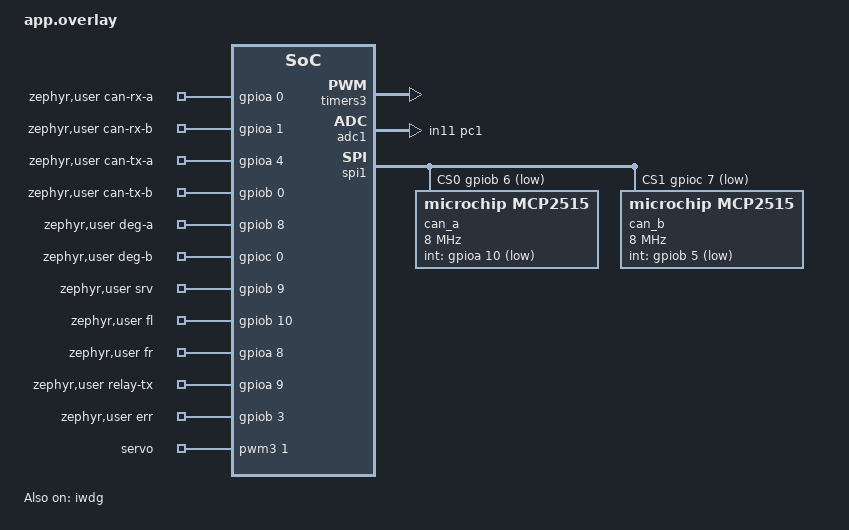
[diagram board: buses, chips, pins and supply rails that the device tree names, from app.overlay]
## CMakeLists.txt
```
cmake_minimum_required(VERSION 3.20.0)

find_package(Zephyr REQUIRED HINTS $ENV{ZEPHYR_BASE})
project(node2_front)

target_include_directories(app PRIVATE ${CMAKE_CURRENT_SOURCE_DIR}/../shared)

target_sources(app PRIVATE
    ${CMAKE_CURRENT_SOURCE_DIR}/../shared/raft_agent.c
    ${CMAKE_CURRENT_SOURCE_DIR}/../shared/raft_transport.c
    # shared with node3_rear (identical files)
    src/main.c
    src/blink.c
    src/button.c
    src/canbus.c
    src/ctrl.c
    src/current_sensor.c
    src/evlog.c
    src/hb.c
    src/relay.c
    src/raft_node.c
    src/report.c
    src/tp.c
    src/wcet.c
    src/jitter.c
    src/watchdog.c
    src/zone.c
    # N2 only: steering zone
    src/servo.c
    src/steer.c
)
```

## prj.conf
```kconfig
CONFIG_GPIO=y
CONFIG_SPI=y
CONFIG_CAN=y
# RX overrun counter in the 1 s summary (ovr=)
CONFIG_STATS=y
CONFIG_CAN_STATS=y
# CONFIG_CAN_MCP2515 is turned on automatically by the mcp2515 nodes in app.overlay
CONFIG_PWM=y
CONFIG_ADC=y
# Independent watchdog (R4.5) and reset-cause readout
CONFIG_WATCHDOG=y
CONFIG_HWINFO=y

CONFIG_CONSOLE=y
CONFIG_UART_CONSOLE=y
CONFIG_PRINTK=y

CONFIG_MAIN_STACK_SIZE=2048

# WCET measurement (src/wcet.c): per-thread CPU time, which stops while a
# thread is preempted or blocked. ANALYSIS adds the driver threads' longest run.
CONFIG_THREAD_RUNTIME_STATS=y
CONFIG_SCHED_THREAD_USAGE=y
CONFIG_SCHED_THREAD_USAGE_ANALYSIS=y
```

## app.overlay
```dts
/*
 * N2 (front, steering): two MCP2515 CAN modules on SPI1, the Lab 2 steering
 * servo and servo current sensor, and the Lab 3 test points.
 * Full pin and breadboard-row map: docs/lab3_pin_map.md
 */
#include <zephyr/dt-bindings/gpio/gpio.h>
#include <zephyr/dt-bindings/pwm/pwm.h>

/ {
	aliases {
		can-a = &can_a;
		can-b = &can_b;
	};

	zephyr,user {
		/* Test points (src/tp.c). Rows 1-2 of the test-point board are GND. */
		can-rx-a-gpios = <&gpioa 0 GPIO_ACTIVE_HIGH>;	/* row 3:  CAN_RX_A, A0 / PA0 */
		can-rx-b-gpios = <&gpioa 1 GPIO_ACTIVE_HIGH>;	/* row 4:  CAN_RX_B, A1 / PA1 */
		can-tx-a-gpios = <&gpioa 4 GPIO_ACTIVE_HIGH>;	/* row 5:  CAN_TX_A, A2 / PA4 */
		can-tx-b-gpios = <&gpiob 0 GPIO_ACTIVE_HIGH>;	/* row 6:  CAN_TX_B, A3 / PB0 */
		deg-a-gpios    = <&gpiob 8 GPIO_ACTIVE_HIGH>;	/* row 7:  DEG_A,    D15 / PB8, LED */
		deg-b-gpios    = <&gpioc 0 GPIO_ACTIVE_HIGH>;	/* row 8:  DEG_B,    A5 / PC0, LED */
		srv-gpios      = <&gpiob 9 GPIO_ACTIVE_HIGH>;	/* row 9:  SRV,      D14 / PB9: toggles on each servo duty set (servo PWM itself: D5 / PB4) */
		fl-gpios       = <&gpiob 10 GPIO_ACTIVE_HIGH>;	/* row 10: FL,       D6 / PB10, LED */
		fr-gpios       = <&gpioa 8 GPIO_ACTIVE_HIGH>;	/* row 11: FR,       D7 / PA8,  LED */
		relay-tx-gpios = <&gpioa 9 GPIO_ACTIVE_HIGH>;	/* row 12: RELAY_TX, D8 / PA9 */
		err-gpios      = <&gpiob 3 GPIO_ACTIVE_HIGH>;	/* row 13: ERR,      D3 / PB3 */

		/* Steering servo (src/servo.c), 50 Hz, as in Lab 2 */
		pwms = <&pwm3 1 PWM_MSEC(20) PWM_POLARITY_NORMAL>;
		pwm-names = "servo";
	};
};

/* ---- Board defaults that sit on pins this node uses ---- */
/* ---- Independent watchdog (src/watchdog.c); the window watchdog stays off ---- */
&iwdg { status = "okay"; };
&wwdg { status = "disabled"; };

&usart1 { status = "disabled"; };	/* PB6/PB7: PB6 is CAN A chip select */
&i2c1 { status = "disabled"; };		/* PB8/PB9: DEG_A, SRV */
&i2c3 { status = "disabled"; };		/* PA8/PC9: PA8 is FR */
&pwm2 { status = "disabled"; };		/* PWM LED on PA5 = SPI1 SCK */
&timers2 { status = "disabled"; };

/* ---- Servo PWM on D5 / PB4 (TIM3_CH1), 1 MHz timer tick (Lab 2) ---- */
&timers3 {
	status = "okay";
	st,prescaler = <83>;

	pwm3: pwm {
		status = "okay";
		pinctrl-0 = <&tim3_ch1_pb4>;
		pinctrl-names = "default";
	};
};

/* ---- Servo current sensor: PC1 = ADC1_IN11 (Lab 2) ---- */
&adc1 {
	pinctrl-0 = <&adc1_in11_pc1>;
	pinctrl-names = "default";
	status = "okay";
};

/*
 * ---- Two XIAO CAN modules (MCP2515 + SN65HVD230) on SPI1 ----
 *
 *   Module   Function   Nucleo
 *   D8       SCK        D13 / PA5   (shared)
 *   D10      MOSI       D11 / PA7   (shared)
 *   D9       MISO       D12 / PA6   (shared)
 *   D7       CS         CAN A: D10 / PB6    CAN B: D9 / PC7
 *   D6       INT        CAN A: D2  / PA10   CAN B: D4 / PB5
 *
 * osc-freq must match the crystal printed on the module's metal can.
 */
&spi1 {
	status = "okay";
	cs-gpios = <&gpiob 6 GPIO_ACTIVE_LOW>,	/* reg 0: CAN A */
		   <&gpioc 7 GPIO_ACTIVE_LOW>;	/* reg 1: CAN B */

	can_a: can@0 {
		compatible = "microchip,mcp2515";
		reg = <0>;
		/*
		 * Requests 8 MHz; SPI1 runs from the 84 MHz APB2 clock with power-of-two
		 * dividers, so the real clock is 84/16 = 5.25 MHz (4 MHz gave 2.625).
		 * Lab 5: N2 relays ~190 frames/s over this shared bus; at 2.625 MHz its
		 * TX completions fell behind and heartbeats found all 3 TX buffers busy.
		 * History: 1 MHz lost back-to-back frames. MCP2515 max is 10 MHz.
		 */
		spi-max-frequency = <8000000>;
		int-gpios = <&gpioa 10 (GPIO_ACTIVE_LOW | GPIO_PULL_UP)>;
		osc-freq = <16000000>;
		bitrate = <500000>;
		status = "okay";
	};

	can_b: can@1 {
		compatible = "microchip,mcp2515";
		reg = <1>;
		spi-max-frequency = <8000000>;
		int-gpios = <&gpiob 5 (GPIO_ACTIVE_LOW | GPIO_PULL_UP)>;
		osc-freq = <16000000>;
		bitrate = <500000>;
		status = "okay";
	};
};
```

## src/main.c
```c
/*
 * Lab 3 zone controller: shared dual-CAN layer, heartbeats, HB_MON with
 * degraded LEDs and zone failure, the N2 relay, test points, and the Lab 2
 * actuators and sensors for this zone (app.h: steer.c on N2, drive.c on N3).
 *
 * Threads (priority, lower = higher; all values in lab3_config.h):
 *   MCP2515 driver x2 (2)  SPI frame reads, toggles CAN_RX_A/B via canbus rx_cb
 *   relay      (3, N2)     forwards first copies to the other bus, RELAY_TX
 *   dispatch   (4)         dedup by (ID, seq), heartbeat ages, CTRL check,
 *                          HB/FAULT -> zone state, BLINK -> blink
 *   steer      (5, N2)     CTRL -> servo angle
 *   drive      (5, N3)     CTRL -> brake / coast / PID target
 *   blink      (5)         this zone's two blinker lamps
 *   test_btn   (5)         USER button B1 -> local fault / recover
 *   pid        (6, N3)     encoders -> motor duty every 10 ms
 *   hb_tx      (7)         HB every 20 ms on both buses
 *   hb_mon     (8)         every 5 ms: DEG_A/B, zone lost, zone state, ERR, watchdog
 *   force      (9, N2)     FORCE every 50 ms
 *   current    (10)        current sensors every 20 ms
 *   report     (12)        console summary once a second
 *
 * Console: USART2 / ST-LINK virtual COM port, 115200 baud.
 */
#include <zephyr/kernel.h>
#include <zephyr/sys/printk.h>

#include "app.h"
#include "blink.h"
#include "button.h"
#include "canbus.h"
#include "ctrl.h"
#include "hb.h"
#include "lab3_config.h"
#include "node_config.h"
#include "raft_node.h"
#include "raft_config.h"
#include "relay.h"
#include "report.h"
#include "tp.h"
#include "watchdog.h"
#include "wcet.h"
#include "zone.h"

/* Dispatch thread: route the first copy of each frame. */
static void on_frame(const struct can_frame *frame, int bus)
{
	if (catalog_is_raft(frame->id)) {
		raft_node_receive(frame);
		return;
	}
	if (frame->id == ID_CTRL) {
		ctrl_on_frame(frame);
	} else if (frame->id == ID_BLINK) {
		blink_on_frame(frame);
	} else if (catalog_is_hb(frame->id) || (frame->id >= ID_FAULT(0) && frame->id < ID_FAULT(NUM_NODES))) {
		zone_on_frame(frame);
	}
	app_on_frame(frame, bus);
}

int main(void)
{
	printk("Lab 3 zone %s: heartbeat 0x%03x every %d ms, relay %s\n", NODE_NAME,
	       ID_HB(NODE_SELF), HB_PERIOD_MS, RELAY_ENABLED ? "on" : "off");

	tp_init();
	wcet_init();
	if (TP_WALK_MS > 0) {
		tp_selftest(TP_WALK_MS);
	}
	/* Power up in the error state with both buses degraded until heartbeats arrive. */
	tp_set(TP_ERR, 1);
	tp_set(TP_DEG_A, 1);
	tp_set(TP_DEG_B, 1);

	canbus_set_handler(on_frame);
	if (canbus_init() < 0) {
		printk("no CAN controller came up\n");
	}
	raft_node_init();
	relay_init();
	hb_init();
	report_init();

	/* Actuators safe, sensors calibrated (~0.75 s), then the zone's tasks. */
	int ret = app_init();

	if (ret < 0) {
		printk("app_init failed (%d): actuators stay in their safe state\n", ret);
	}
	blink_init();
	if (button_init() < 0) {
		printk("test button init failed\n");
	}
	/* Last, and only if the actuator task is running: it has to check in. */
	if (ret == 0) {
		watchdog_init();
	} else {
		printk("watchdog not started (no actuator task to supervise)\n");
	}
	return 0;
}
```

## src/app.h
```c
/*
 * Node-specific application, implemented by steer.c (N2) or drive.c (N3).
 * main.c and report.c are shared and call these.
 */
#ifndef APP_H
#define APP_H

#include <zephyr/drivers/can.h>

/* Puts actuators in their safe state, calibrates sensors, starts the tasks. */
int app_init(void);

/* Called by the dispatch thread with the first copy of each catalog frame. */
void app_on_frame(const struct can_frame *frame, int bus);

/* One or two lines for the once-a-second console summary. */
void app_report(void);

#endif /* APP_H */
```

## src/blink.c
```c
#include "blink.h"

#include <zephyr/kernel.h>
#include <zephyr/sys/atomic.h>

#include "catalog.h"
#include "evlog.h"
#include "hb.h"
#include "lab3_config.h"
#include "node_config.h"
#include "tp.h"
#include "wcet.h"
#include "zone.h"

#define BLINK_STACK_SIZE 1024

static atomic_t last_bits;      /* byte 1 of the last BLINK */
static atomic_t last_rx_ms;     /* 0 = never */
static atomic_t local_hazard;
static atomic_t lamps;          /* bit 0 left, bit 1 right: what's lit now */

K_SEM_DEFINE(blink_new, 0, 1);
K_THREAD_STACK_DEFINE(blink_stack, BLINK_STACK_SIZE);
static struct k_thread blink_data;

void blink_on_frame(const struct can_frame *frame)
{
	uint32_t now = k_uptime_get_32();

	atomic_set(&last_bits, frame->data[1]);
	atomic_set(&last_rx_ms, now != 0 ? now : 1);
	k_sem_give(&blink_new);
}

static void set_lamps(bool left, bool right)
{
	tp_set(BLINK_LAMP_LEFT, left);
	tp_set(BLINK_LAMP_RIGHT, right);
	atomic_set(&lamps, (left ? 1 : 0) | (right ? 2 : 0));
}

static void blink_thread(void *p1, void *p2, void *p3)
{
	uint32_t next_local_toggle = 0;
	bool local_phase = false;
	uint8_t logged_mode = 0;
	struct wcet_job job = WCET_JOB(WCET_BLINK);

	ARG_UNUSED(p1);
	ARG_UNUSED(p2);
	ARG_UNUSED(p3);

	for (;;) {
		/* A frame wakes us at once; otherwise re-check every 10 ms. */
		wcet_end(&job);
		k_sem_take(&blink_new, K_MSEC(10));
		wcet_begin(&job);

		uint32_t now = k_uptime_get_32();
		uint32_t rx = (uint32_t)atomic_get(&last_rx_ms);
		bool hazard_here = zone_state() == ZONE_ISOLATED || !hb_peer_alive(NODE_N1) ||
				   rx == 0 || now - rx > BLINK_STALE_MS;

		if (hazard_here) {
			if (!atomic_get(&local_hazard)) {
				if (zone_state() == ZONE_ISOLATED) {
					evlog("local hazard ON: zone ISOLATED");
				} else if (!hb_peer_alive(NODE_N1)) {
					evlog("local hazard ON: N1 heartbeat lost");
				} else if (rx == 0) {
					evlog("local hazard ON: no BLINK received yet");
				} else {
					evlog("local hazard ON: no BLINK for %u ms", now - rx);
				}
				atomic_set(&local_hazard, 1);
				local_phase = true;
				next_local_toggle = now + BLINK_HALF_MS;
			} else if ((int32_t)(now - next_local_toggle) >= 0) {
				local_phase = !local_phase;
				next_local_toggle += BLINK_HALF_MS;
			}
			set_lamps(local_phase, local_phase);
			continue;
		}
		if (atomic_get(&local_hazard)) {
			evlog("local hazard off");
		}
		atomic_set(&local_hazard, 0);

		uint8_t bits = (uint8_t)atomic_get(&last_bits);
		uint8_t mode = bits & (BLINK_LEFT | BLINK_RIGHT);

		if (mode != logged_mode) {
			static const char *const names[] = {"off", "LEFT", "RIGHT", "HAZARD"};

			evlog("cockpit BLINK %s -> %s", names[logged_mode], names[mode]);
			logged_mode = mode;
		}
		bool on = bits & BLINK_PHASE;

		set_lamps(on && (bits & BLINK_LEFT), on && (bits & BLINK_RIGHT));
	}
}

const char *blink_describe(void)
{
	static const char *const names[] = {"off", "LEFT", "RIGHT", "HAZARD"};
	static char buf[32];
	uint8_t bits = (uint8_t)atomic_get(&last_bits) & (BLINK_LEFT | BLINK_RIGHT);
	bool local = atomic_get(&local_hazard);
	int l = (int)atomic_get(&lamps);

	snprintk(buf, sizeof(buf), "%s%s, lamps %s", local ? "HAZARD" : names[bits],
		 local ? " (local)" : "", l == 3 ? "both on" : (l == 1 ? "L on" : (l == 2 ? "R on" : "off")));
	return buf;
}

int blink_init(void)
{
	k_thread_create(&blink_data, blink_stack, K_THREAD_STACK_SIZEOF(blink_stack), blink_thread,
			NULL, NULL, NULL, PRIO_BLINK, 0, K_NO_WAIT);
	k_thread_name_set(&blink_data, "blink");
	return 0;
}
```

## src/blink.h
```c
/*
 * BLINK_F (N2) / BLINK_R (N3): this zone's two blinker lamps (BLINK_LAMP_LEFT /
 * BLINK_LAMP_RIGHT in node_config.h).
 *
 * Follows the cockpit's BLINK frames: lamp on = its side's bit set and the
 * phase bit set, updated as soon as a frame arrives (both STM32s act on the
 * same frame, which is the front/rear sync). If N1's heartbeat is lost, the
 * zone is ISOLATED, or no BLINK arrives for BLINK_STALE_MS (2.6 s), the zone
 * flashes its own hazards at 1 Hz. A single lost BLINK only delays one edge.
 */
#ifndef BLINK_H
#define BLINK_H

#include <zephyr/drivers/can.h>

int blink_init(void);

/* Dispatch thread, first copy of each BLINK frame. */
void blink_on_frame(const struct can_frame *frame);

/* For the report: "LEFT on", "HAZARD (local) off", ... */
const char *blink_describe(void);

#endif /* BLINK_H */
```

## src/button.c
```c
/*
 * TEST_BTN: the Nucleo's blue USER button B1 (PC13, the board's sw0). The GPIO
 * interrupt only gives a semaphore; this thread debounces (TEST_BTN_DEBOUNCE_MS
 * lockout after an accepted press, so the first edge acts at once) and hands
 * the press to the zone state machine. Single press = local fail, double
 * press = recover (zone.c).
 */
#include "button.h"

#include <zephyr/drivers/gpio.h>
#include <zephyr/kernel.h>
#include <zephyr/sys/printk.h>

#include "lab3_config.h"
#include "wcet.h"
#include "zone.h"

#define BUTTON_STACK_SIZE 1024

static const struct gpio_dt_spec button = GPIO_DT_SPEC_GET(DT_ALIAS(sw0), gpios);
static struct gpio_callback button_cb;

K_SEM_DEFINE(button_sem, 0, 1);
K_THREAD_STACK_DEFINE(button_stack, BUTTON_STACK_SIZE);
static struct k_thread button_data;

static void button_isr(const struct device *dev, struct gpio_callback *cb, uint32_t pins)
{
	ARG_UNUSED(dev);
	ARG_UNUSED(cb);
	ARG_UNUSED(pins);
	k_sem_give(&button_sem);
}

static void button_thread(void *p1, void *p2, void *p3)
{
	uint32_t last_press = 0;
	bool first = true;
	struct wcet_job job = WCET_JOB(WCET_TEST_BTN);

	ARG_UNUSED(p1);
	ARG_UNUSED(p2);
	ARG_UNUSED(p3);

	for (;;) {
		wcet_end(&job);
		k_sem_take(&button_sem, K_FOREVER);
		wcet_begin(&job);

		uint32_t now = k_uptime_get_32();

		if (!first && now - last_press < TEST_BTN_DEBOUNCE_MS) {
			continue; /* contact bounce */
		}
		first = false;
		last_press = now;
		zone_test_button();
	}
}

int button_init(void)
{
	int ret;

	if (!gpio_is_ready_dt(&button)) {
		return -ENODEV;
	}
	ret = gpio_pin_configure_dt(&button, GPIO_INPUT);
	ret = ret ? ret : gpio_pin_interrupt_configure_dt(&button, GPIO_INT_EDGE_TO_ACTIVE);
	if (ret < 0) {
		return ret;
	}
	gpio_init_callback(&button_cb, button_isr, BIT(button.pin));
	gpio_add_callback(button.port, &button_cb);

	k_thread_create(&button_data, button_stack, K_THREAD_STACK_SIZEOF(button_stack),
			button_thread, NULL, NULL, NULL, PRIO_TEST_BTN, 0, K_NO_WAIT);
	k_thread_name_set(&button_data, "test_btn");
	return 0;
}
```

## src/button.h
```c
/* TEST_BTN on the USER button B1 (PC13). */
#ifndef BUTTON_H
#define BUTTON_H

int button_init(void);

#endif /* BUTTON_H */
```

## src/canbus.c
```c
#include "canbus.h"

#include <string.h>

#include <zephyr/kernel.h>
#include <zephyr/sys/printk.h>

#include "lab3_config.h"
#include "node_config.h"
#include "tp.h"
#include "jitter.h"
#include "wcet.h"

#define DISPATCH_STACK_SIZE 1536
#define RX_QUEUE_DEPTH      32

static const struct device *const can_devs[NUM_BUSES] = {
	DEVICE_DT_GET(DT_ALIAS(can_a)),
	DEVICE_DT_GET(DT_ALIAS(can_b)),
};
static const char bus_name[NUM_BUSES] = {'A', 'B'};
static const enum tp_id tp_rx[NUM_BUSES] = {TP_CAN_RX_A, TP_CAN_RX_B};
static const enum tp_id tp_tx[NUM_BUSES] = {TP_CAN_TX_A, TP_CAN_TX_B};

const uint16_t canbus_slot_id[CANBUS_NUM_SLOTS] = {
	ID_CTRL,
	ID_FAULT(NODE_N1), ID_FAULT(NODE_N2), ID_FAULT(NODE_N3),
	ID_HB(NODE_N1), ID_HB(NODE_N2), ID_HB(NODE_N3),
	ID_BLINK,
	ID_FORCE,
};

/* Hardware filters: masks cover the FAULT and HB ranges in one filter each. */
static const struct can_filter catalog_filters[] = {
	{.id = ID_CTRL, .mask = CAN_STD_ID_MASK},
	{.id = ID_FAULT(0), .mask = 0x7FC}, /* 0x020-0x023 */
	{.id = ID_HB(0), .mask = 0x7FC},    /* 0x100-0x103 */
	/* BLINK 0x200 and FORCE 0x300 differ only in bit 8: one filter keeps us at six. */
	{.id = ID_BLINK, .mask = CAN_STD_ID_MASK & ~(ID_BLINK ^ ID_FORCE)},
	{.id = ID_REF(0), .mask = RAFT_REF_FILTER_MASK},          /* 0x040-0x043 */
	{.id = ID_RAFT_BULK_BASE, .mask = RAFT_BULK_FILTER_MASK}, /* 0x140-0x15F */
};

struct canbus_stats canbus_stats;

static bool bus_running[NUM_BUSES];
static atomic_t bus_degraded[NUM_BUSES];
/*
 * Frames handed to the MCP2515 and not yet completed, per bus. The chip has
 * three TX buffers; bulk Raft fragments may use at most RAFT_TX_MAX_INFLIGHT
 * of them, so a heartbeat, CTRL, or FAULT (sent with K_NO_WAIT) always finds
 * one free. REF is a single periodic frame and is not limited.
 */
static atomic_t tx_inflight[NUM_BUSES];
static atomic_t bus_busoff[NUM_BUSES];

static canbus_handler_t relay_hook;
static uint32_t cur_rx_t; /* dispatch thread: t_rx of the frame being handled */
static canbus_handler_t app_handler;

/* Per-ID send sequence counters. */
static uint8_t tx_seq[CANBUS_NUM_SLOTS];
static struct k_spinlock tx_lock;

/* HB_TX and HB_MON can both flush a bus; one stop/start at a time. */
K_MUTEX_DEFINE(flush_lock);

/* Dispatch thread state (only the dispatch thread writes these). */
struct seen {
	int64_t ms;
	uint8_t seq;
	bool valid;
};
static struct seen seen[CANBUS_NUM_SLOTS];
struct raft_recent {
	uint32_t id;
	int64_t ms;
	uint8_t data[FRAME_DLC];
};
static struct raft_recent raft_recent[32];
static uint8_t raft_recent_next;
/* 32-bit so other threads read it in one access; 0 = never heard. */
static uint32_t last_hb_ms[NUM_BUSES][NUM_NODES];

struct rx_item {
	uint8_t bus;
	uint32_t t_rx; /* k_cycle_get_32() in rx_cb */
	struct can_frame frame;
};
K_MSGQ_DEFINE(rx_q, sizeof(struct rx_item), RX_QUEUE_DEPTH, 4);

K_THREAD_STACK_DEFINE(dispatch_stack, DISPATCH_STACK_SIZE);
static struct k_thread dispatch_thread_data;

static int slot_of(uint32_t id)
{
	for (int i = 0; i < CANBUS_NUM_SLOTS; i++) {
		if (canbus_slot_id[i] == id) {
			return i;
		}
	}
	return -1;
}

static bool raft_duplicate(const struct can_frame *f, int64_t now)
{
	for (size_t i = 0; i < ARRAY_SIZE(raft_recent); i++) {
		if (raft_recent[i].id == f->id && now - raft_recent[i].ms < DUP_WINDOW_MS &&
		    memcmp(raft_recent[i].data, f->data, FRAME_DLC) == 0) {
			return true;
		}
	}
	struct raft_recent *r = &raft_recent[raft_recent_next++ % ARRAY_SIZE(raft_recent)];

	r->id = f->id;
	r->ms = now;
	memcpy(r->data, f->data, FRAME_DLC);
	return false;
}

const struct device *canbus_dev(int bus)
{
	return can_devs[bus];
}

/* MCP2515 driver thread, right after the SPI read: no printing, just queue it. */
static void rx_cb(const struct device *dev, struct can_frame *frame, void *user_data)
{
	struct rx_item item = {.bus = (uint8_t)(uintptr_t)user_data, .frame = *frame};

	ARG_UNUSED(dev);
	item.t_rx = jit_now();
	tp_toggle(tp_rx[item.bus]);
	wcet_driver_seen(item.bus);
	if (k_msgq_put(&rx_q, &item, K_NO_WAIT) != 0) {
		atomic_inc(&canbus_stats.rx_dropped);
	}
}

static void tx_cb(const struct device *dev, int error, void *user_data)
{
	int bus = (int)(uintptr_t)user_data;

	ARG_UNUSED(dev);
	if (atomic_dec(&tx_inflight[bus]) <= 0) {
		atomic_set(&tx_inflight[bus], 0); /* never below zero after a flush */
	}
	atomic_inc(error == 0 ? &canbus_stats.bus[bus].tx_ok : &canbus_stats.bus[bus].tx_err);
}

/* Counts the buffer before can_send() so tx_cb can never run first. */
static int send_counted(int bus, const struct can_frame *frame, k_timeout_t wait)
{
	struct canbus_bus_stats *b = &canbus_stats.bus[bus];
	atomic_val_t now = atomic_inc(&tx_inflight[bus]) + 1;

	if (now > atomic_get(&b->infl_max)) {
		atomic_set(&b->infl_max, now);
	}
	int ret = can_send(can_devs[bus], frame, wait, tx_cb, (void *)(uintptr_t)bus);

	if (ret < 0) {
		atomic_dec(&tx_inflight[bus]);
	} else {
		atomic_inc(&b->tx_queued);
	}
	return ret;
}

static bool is_raft_bulk(uint32_t id)
{
	return catalog_is_raft(id) && (id & ~3u) != ID_REF(0);
}

bool canbus_raft_tx_ready(int bus)
{
	return atomic_get(&tx_inflight[bus]) < RAFT_TX_MAX_INFLIGHT;
}

bool canbus_raft_wait_reserve(int bus)
{
	uint32_t start = k_cycle_get_32();

	while (!canbus_raft_tx_ready(bus)) {
		if (k_cyc_to_us_floor32(k_cycle_get_32() - start) >= RAFT_TX_RESERVE_WAIT_US) {
			return false;
		}
		k_sleep(K_USEC(100));
	}
	return true;
}

long canbus_tx_inflight(int bus)
{
	return (long)atomic_get(&tx_inflight[bus]);
}

static void state_cb(const struct device *dev, enum can_state state, struct can_bus_err_cnt err,
		     void *user_data)
{
	ARG_UNUSED(dev);
	ARG_UNUSED(err);
	if (state == CAN_STATE_BUS_OFF) {
		atomic_set(&bus_busoff[(int)(uintptr_t)user_data], 1);
	}
}

static void dispatch_thread(void *p1, void *p2, void *p3)
{
	struct rx_item item;
	struct wcet_job job = WCET_JOB(WCET_DISPATCH);

	ARG_UNUSED(p1);
	ARG_UNUSED(p2);
	ARG_UNUSED(p3);

	for (;;) {
		wcet_end(&job);
		k_msgq_get(&rx_q, &item, K_FOREVER);
		wcet_begin(&job);

		const struct can_frame *f = &item.frame;

		job.slot = f->id == ID_CTRL ? WCET_DISPATCH_CTRL : WCET_DISPATCH;
		int slot = slot_of(f->id);
		int sender = catalog_sender(f->id);
		int64_t now = k_uptime_get();
		if (catalog_is_raft(f->id) && f->dlc == FRAME_DLC) {
			if (sender == NODE_SELF) {
				atomic_inc(&canbus_stats.own_echo);
			} else if (raft_duplicate(f, now)) {
				atomic_inc(&canbus_stats.duplicates);
			} else {
				cur_rx_t = item.t_rx;
				if (relay_hook) {
					relay_hook(f, item.bus);
				}
				if (app_handler) {
					app_handler(f, item.bus);
				}
			}
			continue;
		}

		if (slot < 0 || f->dlc != FRAME_DLC) {
			atomic_inc(&canbus_stats.unknown_id);
			continue;
		}
		atomic_inc(&canbus_stats.bus[item.bus].rx[slot]);

		/* Our own frame, relayed back to us by N2. */
		if (sender == NODE_SELF) {
			atomic_inc(&canbus_stats.own_echo);
			continue;
		}

		/* Presence counts every copy: a relayed heartbeat still means "alive". */
		if (catalog_is_hb(f->id)) {
			uint32_t t = (uint32_t)now;

			last_hb_ms[item.bus][sender] = t != 0 ? t : 1;
		}

		uint8_t seq = f->data[0] & SEQ_MASK;
		struct seen *s = &seen[slot];

		if (s->valid && s->seq == seq && now - s->ms < DUP_WINDOW_MS) {
			atomic_inc(&canbus_stats.duplicates);
			continue;
		}
		if (s->valid && seq != ((s->seq + 1) & SEQ_MASK)) {
			atomic_add(&canbus_stats.gaps[slot], (seq - s->seq - 1) & SEQ_MASK);
		}
		s->seq = seq;
		s->ms = now;
		s->valid = true;
		atomic_inc(&canbus_stats.accepted[slot]);

		cur_rx_t = item.t_rx;
		if (relay_hook) {
			relay_hook(f, item.bus);
		}
		if (app_handler) {
			app_handler(f, item.bus);
		}
	}
}

uint32_t canbus_rx_cycles(void)
{
	return cur_rx_t;
}

static int queue_on(int bus, const struct can_frame *frame, uint32_t release, bool relayed,
		    k_timeout_t wait)
{
	int ret;

	tp_toggle(tp_tx[bus]);
	ret = send_counted(bus, frame, wait);
	if (ret == 0) {
		jit_note(frame->id, bus, release, relayed);
	}
	if (ret == -EAGAIN) {
		atomic_inc(&canbus_stats.bus[bus].tx_full); /* all 3 TX buffers busy */
	} else if (ret < 0) {
		atomic_inc(&canbus_stats.bus[bus].tx_err);
	}
	return ret;
}

int canbus_send(uint32_t id, uint8_t payload[FRAME_DLC], bool include_degraded)
{
	return canbus_send_at(id, payload, include_degraded, 0);
}

int canbus_send_raft(uint32_t id, const uint8_t payload[FRAME_DLC])
{
	struct can_frame frame = {.id = id, .dlc = FRAME_DLC};
	int sent = 0;

	if (!catalog_is_raft(id) || catalog_sender(id) != NODE_SELF) {
		return -EINVAL;
	}
	memcpy(frame.data, payload, FRAME_DLC);
	for (int bus = 0; bus < NUM_BUSES; bus++) {
		if (!bus_running[bus] || atomic_get(&bus_degraded[bus])) {
			continue;
		}
		/*
		 * Prefer to leave the last TX buffer to Lab 3 frames, but never skip a
		 * fragment for it: a missing fragment loses the whole message.
		 */
		if (is_raft_bulk(id) && !canbus_raft_wait_reserve(bus)) {
			atomic_inc(&canbus_stats.bus[bus].raft_late);
		}
		tp_toggle(tp_tx[bus]);
		int ret = send_counted(bus, &frame, K_MSEC(2));
		if (ret == 0) {
			sent++;
		} else if (ret == -EAGAIN) {
			atomic_inc(&canbus_stats.bus[bus].tx_full);
		} else {
			atomic_inc(&canbus_stats.bus[bus].tx_err);
		}
	}
	return sent ? 0 : -EIO;
}

int canbus_send_at(uint32_t id, uint8_t payload[FRAME_DLC], bool include_degraded,
		   uint32_t release)
{
	int slot = slot_of(id);
	struct can_frame frame = {.id = id, .dlc = FRAME_DLC};
	int sent = 0;

	if (slot < 0) {
		return -EINVAL;
	}

	k_spinlock_key_t key = k_spin_lock(&tx_lock);
	payload[0] = tx_seq[slot] & SEQ_MASK; /* flags nibble: none defined */
	tx_seq[slot] = (tx_seq[slot] + 1) & SEQ_MASK;
	k_spin_unlock(&tx_lock, key);

	memcpy(frame.data, payload, FRAME_DLC);

	for (int bus = 0; bus < NUM_BUSES; bus++) {
		if (!bus_running[bus]) {
			continue;
		}
		if (!include_degraded && atomic_get(&bus_degraded[bus])) {
			atomic_inc(&canbus_stats.bus[bus].tx_skipped);
			continue;
		}
		/*
		 * Our heartbeat may wait briefly for a TX buffer: the driver frees a
		 * buffer a little after its TX callback, so K_NO_WAIT sometimes found
		 * none free and the heartbeat was lost. Not on a degraded bus, where
		 * unACKed heartbeats can hold every buffer and waiting cannot help.
		 */
		k_timeout_t wait = catalog_is_hb(id) && !atomic_get(&bus_degraded[bus]) ?
					   K_USEC(HB_TX_WAIT_US) : K_NO_WAIT;

		if (queue_on(bus, &frame, release, false, wait) == 0) {
			sent++;
		}
	}
	return sent > 0 ? 0 : -EIO;
}

int canbus_forward(int bus, const struct can_frame *frame)
{
	return canbus_forward_at(bus, frame, 0);
}

int canbus_forward_at(int bus, const struct can_frame *frame, uint32_t release)
{
	if (!bus_running[bus]) {
		return -ENETDOWN;
	}
	if (atomic_get(&bus_degraded[bus])) {
		atomic_inc(&canbus_stats.bus[bus].tx_skipped);
		return -ENETUNREACH;
	}
	return queue_on(bus, frame, release, true, K_NO_WAIT);
}

void canbus_flush(int bus)
{
	if (!bus_running[bus]) {
		return;
	}
	/* can_stop() aborts pending transmissions; restart keeps the filters. */
	k_mutex_lock(&flush_lock, K_FOREVER);
	can_stop(can_devs[bus]);
	atomic_set(&tx_inflight[bus], 0); /* stop aborted everything pending */
	can_start(can_devs[bus]);
	k_mutex_unlock(&flush_lock);
}

bool canbus_bus_running(int bus)
{
	return bus_running[bus];
}

void canbus_set_degraded(int bus, bool degraded)
{
	atomic_set(&bus_degraded[bus], degraded ? 1 : 0);
}

bool canbus_is_degraded(int bus)
{
	return atomic_get(&bus_degraded[bus]) != 0;
}

uint32_t canbus_last_hb_ms(int bus, int node)
{
	return last_hb_ms[bus][node];
}

bool canbus_take_busoff(int bus)
{
	return atomic_clear(&bus_busoff[bus]) != 0;
}

void canbus_set_relay_hook(canbus_handler_t hook)
{
	relay_hook = hook;
}

void canbus_set_handler(canbus_handler_t handler)
{
	app_handler = handler;
}

static int setup_bus(int bus)
{
	const struct device *dev = can_devs[bus];
	int ret;

	if (!device_is_ready(dev)) {
		printk("CAN %c (%s): not ready - check SPI wiring, CS pin and osc-freq\n",
		       bus_name[bus], dev->name);
		return -ENODEV;
	}

	for (size_t i = 0; i < ARRAY_SIZE(catalog_filters); i++) {
		ret = can_add_rx_filter(dev, rx_cb, (void *)(uintptr_t)bus, &catalog_filters[i]);
		if (ret < 0) {
			printk("CAN %c: can_add_rx_filter failed (%d)\n", bus_name[bus], ret);
			return ret;
		}
	}
	/*
	 * Deprecated in Zephyr 4.5 in favour of can_add_state_change_callback(),
	 * which older 4.4 trees don't have yet; this one works in both.
	 */
	can_set_state_change_callback(dev, state_cb, (void *)(uintptr_t)bus);

	ret = can_start(dev);
	if (ret < 0) {
		printk("CAN %c: can_start failed (%d)\n", bus_name[bus], ret);
		return ret;
	}
	printk("CAN %c (%s): started\n", bus_name[bus], dev->name);
	return 0;
}

int canbus_init(void)
{
	int up = 0;

	k_thread_create(&dispatch_thread_data, dispatch_stack,
			K_THREAD_STACK_SIZEOF(dispatch_stack), dispatch_thread, NULL, NULL, NULL,
			PRIO_DISPATCH, 0, K_NO_WAIT);
	k_thread_name_set(&dispatch_thread_data, "dispatch");

	for (int bus = 0; bus < NUM_BUSES; bus++) {
		bus_running[bus] = (setup_bus(bus) == 0);
		atomic_set(&bus_degraded[bus], 1); /* until a heartbeat is heard */
		up += bus_running[bus];
	}
	return up > 0 ? 0 : -ENODEV;
}
```

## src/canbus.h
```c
/*
 * Shared dual-CAN layer.
 *
 *  - Both MCP2515 controllers, with receive filters for the catalog IDs only.
 *  - canbus_send(): queues one frame on bus A and bus B back to back with the
 *    same per-ID sequence number, bumped once.
 *  - One dispatch thread that drops duplicates by (ID, seq) - the A copy, the
 *    B copy and any relayed copy - before anything else sees the frame, and
 *    records when each node's heartbeat was last heard on each bus.
 */
#ifndef CANBUS_H
#define CANBUS_H

#include <stdbool.h>
#include <stdint.h>
#include <zephyr/drivers/can.h>
#include <zephyr/sys/atomic.h>

#include "catalog.h"

enum { BUS_A = 0, BUS_B = 1, NUM_BUSES = 2 };

/* Called from the dispatch thread with the first copy of each frame. */
typedef void (*canbus_handler_t)(const struct can_frame *frame, int bus);

int canbus_init(void);

/* Receivers of first copies. The relay hook runs before the application handler. */
void canbus_set_relay_hook(canbus_handler_t hook);
void canbus_set_handler(canbus_handler_t handler);

/*
 * Sends payload (bytes 1-7 used; byte 0 is overwritten with the sequence
 * number) on both buses. Buses marked degraded are skipped unless
 * include_degraded is set (heartbeats keep going out so the link can recover).
 */
int canbus_send(uint32_t id, uint8_t payload[FRAME_DLC], bool include_degraded);

/*
 * Same, recording J = now - release (k_cycle_get_32() of the triggering event,
 * from jit_now()) per bus once each copy is queued. release 0 records nothing.
 */
int canbus_send_at(uint32_t id, uint8_t payload[FRAME_DLC], bool include_degraded,
		   uint32_t release);

/* Sends one raw Lab 5 frame without overwriting byte 0 with a Lab 3 sequence. */
/*
 * True while bulk Raft frames may use another TX buffer on this bus: at most
 * RAFT_TX_MAX_INFLIGHT of the MCP2515's three, so Lab 3 frames keep one.
 */
bool canbus_raft_tx_ready(int bus);

/*
 * Wait up to RAFT_TX_RESERVE_WAIT_US for canbus_raft_tx_ready(). Returns
 * false on timeout; the caller then sends anyway (fail-safe: a Raft message
 * is never abandoned part-way because of the reserve).
 */
bool canbus_raft_wait_reserve(int bus);

/* Frames handed to the MCP2515 and not yet completed (debug). */
long canbus_tx_inflight(int bus);
int canbus_send_raft(uint32_t id, const uint8_t payload[FRAME_DLC]);

/* Queues a bit-identical copy of frame on one bus (the relay). */
int canbus_forward(int bus, const struct can_frame *frame);
int canbus_forward_at(int bus, const struct can_frame *frame, uint32_t release);

/* In a relay hook / handler: k_cycle_get_32() when rx_cb got this frame. */
uint32_t canbus_rx_cycles(void);

/* Aborts every transmission still pending on bus (stale frames on a dead link). */
void canbus_flush(int bus);

bool canbus_bus_running(int bus);
void canbus_set_degraded(int bus, bool degraded);
bool canbus_is_degraded(int bus);

/*
 * k_uptime_get_32() of the last heartbeat from node on bus (any copy, relayed
 * or not); 0 = never heard.
 */
uint32_t canbus_last_hb_ms(int bus, int node);

/* True once if the controller went bus-off since the last call. */
bool canbus_take_busoff(int bus);

/* ---- statistics, read and cleared by the report thread ---- */
#define CANBUS_NUM_SLOTS 9 /* catalog IDs */

struct canbus_bus_stats {
	atomic_t rx[CANBUS_NUM_SLOTS]; /* every copy received on this bus */
	atomic_t tx_ok, tx_err, tx_full, tx_skipped;
	atomic_t tx_queued; /* can_send() accepted; should equal tx_ok + tx_err */
	atomic_t raft_late; /* Raft sent without the reserve: none free within the wait */
	atomic_t infl_max;  /* most frames in flight seen at a send */
};

struct canbus_stats {
	struct canbus_bus_stats bus[NUM_BUSES];
	atomic_t accepted[CANBUS_NUM_SLOTS]; /* first copies */
	atomic_t gaps[CANBUS_NUM_SLOTS];     /* sequence numbers never received */
	atomic_t duplicates, own_echo, unknown_id, rx_dropped;
};

extern struct canbus_stats canbus_stats;
extern const uint16_t canbus_slot_id[CANBUS_NUM_SLOTS];
const struct device *canbus_dev(int bus);

#endif /* CANBUS_H */
```

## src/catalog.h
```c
/* Zephyr-specific CTRL helpers. Wire definitions live in shared/protocol.h. */
#ifndef CATALOG_H
#define CATALOG_H

#include <zephyr/sys/byteorder.h>
#include "protocol.h"
#include "raft_wire.h"

/* Fills bytes 1-7; call after byte 0 (sequence) is set, since the CRC covers it. */
static inline void ctrl_encode(const struct ctrl_cmd *cmd, uint8_t data[FRAME_DLC])
{
	sys_put_le16((uint16_t)cmd->steer, &data[1]);
	data[3] = cmd->throttle;
	data[4] = cmd->brake;
	data[5] = cmd->buttons;
	data[6] = crc8_j1850(data, CTRL_CRC_LEN);
	data[7] = 0;
}

static inline void ctrl_decode(const uint8_t data[FRAME_DLC], struct ctrl_cmd *cmd)
{
	cmd->steer = (int16_t)sys_get_le16(&data[1]);
	cmd->throttle = data[3];
	cmd->brake = data[4];
	cmd->buttons = data[5];
}

/*
 * Validates a received CTRL payload: FAULT_NONE if usable, else the Lab 1
 * fault code to report (CTRL_MALFORMED for a bad CRC or reserved bits,
 * CTRL_RANGE for an out-of-range value). Every uint8 pedal value is valid.
 */
static inline enum fault_code ctrl_check(const uint8_t data[FRAME_DLC], struct ctrl_cmd *cmd)
{
	if (crc8_j1850(data, CTRL_CRC_LEN) != data[6] || data[7] != 0) {
		return FAULT_CTRL_MALFORMED;
	}
	ctrl_decode(data, cmd);
	if (cmd->steer < CTRL_STEER_MIN || cmd->steer > CTRL_STEER_MAX ||
	    (cmd->buttons & ~CTRL_BTN_MASK) != 0) {
		return FAULT_CTRL_RANGE;
	}
	return FAULT_NONE;
}

#endif /* CATALOG_H */
```

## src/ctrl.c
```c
#include "ctrl.h"

#include "lab3_config.h"
#include "zone.h"

struct ctrl_stats ctrl_stats;

static struct k_spinlock lock;
static struct ctrl_cmd latest;
static uint32_t latest_ms;
static bool have;

K_SEM_DEFINE(ctrl_new, 0, 1);

void ctrl_on_frame(const struct can_frame *frame)
{
	struct ctrl_cmd cmd;
	enum fault_code fault = ctrl_check(frame->data, &cmd);

	if (fault != FAULT_NONE) {
		/* Keep the old command; the zone goes to error and sends FAULT_Nx. */
		atomic_inc(fault == FAULT_CTRL_MALFORMED ? &ctrl_stats.malformed
							 : &ctrl_stats.out_of_range);
		atomic_set(&ctrl_stats.last_fault, fault);
		zone_ctrl_rejected(fault);
		k_sem_give(&ctrl_new); /* wake the actuator task: go safe now */
		return;
	}

	k_spinlock_key_t key = k_spin_lock(&lock);
	latest = cmd;
	latest_ms = k_uptime_get_32();
	have = true;
	k_spin_unlock(&lock, key);

	atomic_inc(&ctrl_stats.ok);
	zone_ctrl_accepted();
	k_sem_give(&ctrl_new);
}

void ctrl_kick(void)
{
	k_sem_give(&ctrl_new);
}

bool ctrl_get(struct ctrl_cmd *cmd, uint32_t *age_ms)
{
	k_spinlock_key_t key = k_spin_lock(&lock);
	bool ok = have;

	if (ok) {
		*cmd = latest;
		*age_ms = k_uptime_get_32() - latest_ms;
	}
	k_spin_unlock(&lock, key);
	return ok;
}

bool ctrl_fresh(void)
{
	struct ctrl_cmd cmd;
	uint32_t age;

	return ctrl_get(&cmd, &age) && age < CTRL_TIMEOUT_MS;
}

bool ctrl_wait(k_timeout_t timeout)
{
	return k_sem_take(&ctrl_new, timeout) == 0;
}
```

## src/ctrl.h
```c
/*
 * Latest valid CTRL command, shared by the dispatch thread (writer) and the
 * node's actuator task (DRIVE on N3, STEER on N2). ctrl_on_frame() runs in
 * dispatch; a valid frame wakes the actuator task right away (brake path).
 */
#ifndef CTRL_H
#define CTRL_H

#include <stdbool.h>
#include <stdint.h>
#include <zephyr/drivers/can.h>
#include <zephyr/kernel.h>
#include <zephyr/sys/atomic.h>

#include "catalog.h"

void ctrl_on_frame(const struct can_frame *frame);

/* Copies the latest valid command and its age in ms; false if none yet. */
bool ctrl_get(struct ctrl_cmd *cmd, uint32_t *age_ms);

/* True if a valid command arrived less than CTRL_TIMEOUT_MS ago. */
bool ctrl_fresh(void);

/* Blocks until a new valid command arrives or timeout; true if one arrived. */
bool ctrl_wait(k_timeout_t timeout);

/* Wakes the actuator task early (e.g. the zone just left NORMAL). */
void ctrl_kick(void);

struct ctrl_stats {
	atomic_t ok, malformed, out_of_range;
	atomic_t last_fault; /* enum fault_code of the last rejected frame */
};
extern struct ctrl_stats ctrl_stats;

#endif /* CTRL_H */
```

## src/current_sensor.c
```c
/* Ported from Lab 2 src/drivers/current_sensor.c and src/tasks/current_sensing.c. */
#include "current_sensor.h"

#include <errno.h>

#include <zephyr/device.h>
#include <zephyr/drivers/adc.h>
#include <zephyr/kernel.h>
#include <zephyr/sys/atomic.h>
#include <zephyr/sys/printk.h>
#include <zephyr/sys/util.h>

#include "lab3_config.h"
#include "node_config.h"

#define ADC_REFERENCE_MV     3300
#define ADC_COUNTS           4096
#define DIVIDER_FACTOR       2
#define SENSITIVITY_MV_PER_A 185

#define ZERO_SAMPLES 128
#define READ_SAMPLES 16
#define RAW_SCALE    256

#define CURRENT_STACK_SIZE 1024

static const struct current_channel channels[] = CURRENT_CHANNELS;
#define NUM_CHANNELS ARRAY_SIZE(channels)

static const struct device *const adc_dev = DEVICE_DT_GET(DT_NODELABEL(adc1));

static int32_t zero_scaled[NUM_CHANNELS];
static atomic_t latest_ma[NUM_CHANNELS];
static atomic_t have_reading;

K_THREAD_STACK_DEFINE(current_stack, CURRENT_STACK_SIZE);
static struct k_thread current_data;

static int read_channel(uint8_t channel, int16_t *sample)
{
	struct adc_sequence sequence = {
		.channels = BIT(channel),
		.buffer = sample,
		.buffer_size = sizeof(*sample),
		.resolution = 12,
	};

	return adc_read(adc_dev, &sequence);
}

static int32_t convert_to_ma(int32_t raw_scaled, int i)
{
	int64_t delta = (int64_t)raw_scaled - zero_scaled[i];
	int64_t numerator = delta * ADC_REFERENCE_MV * DIVIDER_FACTOR * 1000 * channels[i].polarity;
	int64_t denominator = (int64_t)RAW_SCALE * ADC_COUNTS * SENSITIVITY_MV_PER_A;

	return (int32_t)(numerator / denominator);
}

static void current_thread(void *p1, void *p2, void *p3)
{
	int64_t next = k_uptime_get();

	ARG_UNUSED(p1);
	ARG_UNUSED(p2);
	ARG_UNUSED(p3);

	for (;;) {
		int32_t sums[NUM_CHANNELS] = {0};
		int16_t sample;
		int ret = 0;

		for (int n = 0; n < READ_SAMPLES && ret == 0; n++) {
			for (size_t i = 0; i < NUM_CHANNELS && ret == 0; i++) {
				ret = read_channel(channels[i].adc_channel, &sample);
				sums[i] += sample;
			}
		}
		if (ret == 0) {
			for (size_t i = 0; i < NUM_CHANNELS; i++) {
				atomic_set(&latest_ma[i],
					   convert_to_ma(sums[i] * RAW_SCALE / READ_SAMPLES, i));
			}
			atomic_set(&have_reading, 1);
		}

		next += CURRENT_PERIOD_MS;
		k_sleep(K_TIMEOUT_ABS_MS(next));
	}
}

int current_sensor_init(void)
{
	int32_t sums[NUM_CHANNELS] = {0};
	int16_t sample;
	int ret;

	if (!device_is_ready(adc_dev)) {
		return -ENODEV;
	}

	for (size_t i = 0; i < NUM_CHANNELS; i++) {
		struct adc_channel_cfg config = {
			.gain = ADC_GAIN_1,
			.reference = ADC_REF_INTERNAL,
			.acquisition_time = ADC_ACQ_TIME(ADC_ACQ_TIME_TICKS, 480),
			.channel_id = channels[i].adc_channel,
		};

		ret = adc_channel_setup(adc_dev, &config);
		if (ret != 0) {
			return ret;
		}
	}

	printk("Calibrating current sensors (no load current)\n");
	k_msleep(100);
	for (int n = 0; n < ZERO_SAMPLES; n++) {
		for (size_t i = 0; i < NUM_CHANNELS; i++) {
			ret = read_channel(channels[i].adc_channel, &sample);
			if (ret != 0) {
				return ret;
			}
			sums[i] += sample;
		}
		k_msleep(5);
	}
	printk("Zero counts:");
	for (size_t i = 0; i < NUM_CHANNELS; i++) {
		zero_scaled[i] = sums[i] * RAW_SCALE / ZERO_SAMPLES;
		printk(" %s=%d", channels[i].name, (int)(zero_scaled[i] / RAW_SCALE));
	}
	printk("\n");

	k_thread_create(&current_data, current_stack, K_THREAD_STACK_SIZEOF(current_stack),
			current_thread, NULL, NULL, NULL, PRIO_CURRENT, 0, K_NO_WAIT);
	k_thread_name_set(&current_data, "current");
	return 0;
}

int current_sensor_count(void)
{
	return NUM_CHANNELS;
}

const char *current_sensor_name(int i)
{
	return channels[i].name;
}

bool current_sensor_get_ma(int i, int32_t *ma)
{
	*ma = (int32_t)atomic_get(&latest_ma[i]);
	return atomic_get(&have_reading) != 0;
}
```

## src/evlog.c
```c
#include "evlog.h"

#include <stdarg.h>
#include <zephyr/kernel.h>
#include <zephyr/sys/printk.h>

#include "lab3_config.h"
#include "node_config.h"

#define EVLOG_TEXT  80
#define EVLOG_DEPTH 16

struct evlog_item {
	uint32_t ms;
	char text[EVLOG_TEXT];
};

K_MSGQ_DEFINE(evlog_q, sizeof(struct evlog_item), EVLOG_DEPTH, 4);
atomic_t evlog_dropped;

void evlog(const char *fmt, ...)
{
	struct evlog_item item = {.ms = k_uptime_get_32()};
	va_list ap;

	va_start(ap, fmt);
	vsnprintk(item.text, sizeof(item.text), fmt, ap);
	va_end(ap);
	if (k_msgq_put(&evlog_q, &item, K_NO_WAIT) != 0) {
		atomic_inc(&evlog_dropped);
	}
}

static void evlog_thread(void *p1, void *p2, void *p3)
{
	struct evlog_item item;

	ARG_UNUSED(p1);
	ARG_UNUSED(p2);
	ARG_UNUSED(p3);

	for (;;) {
		k_msgq_get(&evlog_q, &item, K_FOREVER);
		printk("[%s %u.%03us] >> %s\n", NODE_NAME, item.ms / 1000, item.ms % 1000, item.text);
	}
}

K_THREAD_DEFINE(evlog_tid, 1024, evlog_thread, NULL, NULL, NULL, PRIO_EVLOG, 0, 0);
```
